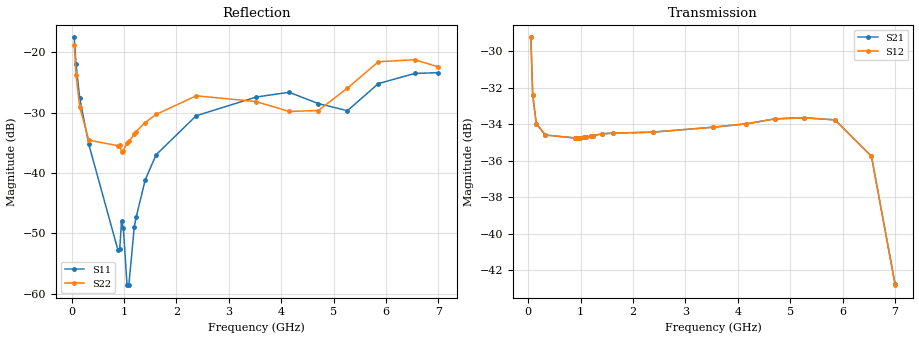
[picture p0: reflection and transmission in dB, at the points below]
! Integrated Device Technology
! Corporate Headquarters
! 6024 Silver Creek Valley Road
! San Jose, CA 95138  USA
! Phone:  1-408-284-8200
! Toll Free:  1-800-223-1366
! Webpage:  http://www.idt.com/
! Timing and RF Division
! 515 Groton Road, Suite 102
! Westford, MA 01886-6024
! Device:  F2258
! Description: Voltage Variable RF Attenuator
! Frequency:  50.0 -  6000.00 MHz
! Package:  3x3 mm Thin QFN Plastic Package: 16 pin
! Ports:  2 RF, 2 DC
!  Pin  1  = NC
!  Pin  2  = NC
!  Pin  3  = RF2  = Port 2
!  Pin  4  = GND
!  Pin  5  = Vdd
!  Pin  6  = NC
!  Pin  7  = VCTRL
!  Pin  8  = NC
!  Pin  9  = GND
!  Pin 10  = RF1  = Port 1
!  Pin 11  = NC
!  Pin 12  = NC
!  Pin 13  = NC
!  Pin 14  = NC
!  Pin 15  = NC
!  Pin 16  = NC
! Vcntrl:  1.940 Volts
! Vdd:  +3.300 Volts
! Current:  1.156 mA
! Data:  The device was measured on a the F2258 evaluation board which has
!  individual transmission lines to the RF pins.  Data was collected
!  using a calibrated network analyzer.  The evaluation board was
!  de-embedded using a TRL calibration technique.
!  The reference plane is the edge of the package pin.
! Misc:  SN 10
!  Action Tracker AT0285
! Date Measured:  2014-12-10
! Date:  2016-01-13  MJV
! Note:
!  Integrated Device Technology supplies this data as a sample of measured
!  data at the package pin for this product.  Your particular data for this
!  product may vary.
!  Data was taken at 25 degrees C.
!  Integrated Device Technology reserves the right to change this data at anytime.
!Freq_(GHz)  S11M_(dB)  S11P_(deg)  S21M_(dB)  S21P_(deg)  S12M_(dB)  S12P_(deg)  S22M_(dB)  S22P_(deg)
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# GHz S dB R 50
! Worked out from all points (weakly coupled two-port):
!   201 points, 50 MHz to 7 GHz, reference 50 ohm
!   highest |S21| = -29.24 dB at 50 MHz (marker M1); lowest = -42.8 dB at 7 GHz (marker M2)
!   lowest |S11| = -58.6 dB at 1.093 GHz (marker M3), VSWR 1.00, Z = 50 + j0.108 ohm
!   |S11| at or under -10 dB: start of sweep to end of sweep
!   |S22| runs from -36.5 to -18.8 dB; largest |S21 - S12| = 7.6e-05
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0.05  -17.55 -110.8  -29.24 -65.6  -29.24 -65.6  -18.84 -106.0
0.08475  -21.97 -107.3  -32.39 -46.3  -32.38 -46.3  -23.71 -93.8
0.15425  -27.56 -107.7  -33.97 -28.1  -33.97 -28.1  -29.05 -77.8
0.328  -35.25 -114.5  -34.59 -14.9  -34.59 -14.9  -34.56 -44.1
0.884  -52.74 166.5  -34.75 -8.8  -34.74 -8.8  -35.48 5.8
0.91875  -52.60 149.3  -34.74 -8.7  -34.74 -8.8  -35.44 6.6
0.9535  -47.87 -161.0  -34.75 -8.7  -34.74 -8.7  -36.49 16.7
0.98825  -49.13 -173.0  -34.73 -8.6  -34.73 -8.6  -36.29 14.9
1.05775  -58.54 155.9  -34.72 -8.5  -34.71 -8.5  -35.10 15.3
1.0925  -58.56 113.8  -34.70 -8.5  -34.69 -8.5  -34.76 15.3
1.19675  -48.86 54.7  -34.66 -8.7  -34.65 -8.7  -33.59 15.3
1.2315  -47.36 45.2  -34.63 -8.6  -34.63 -8.7  -33.14 14.7
1.40525  -41.12 33.0  -34.52 -9.4  -34.52 -9.4  -31.64 15.9
1.61375  -36.97 32.2  -34.49 -10.5  -34.48 -10.5  -30.30 13.7
2.37825  -30.52 47.9  -34.43 -14.5  -34.43 -14.5  -27.22 16.8
3.525  -27.42 91.5  -34.16 -21.5  -34.16 -21.4  -28.18 41.7
4.1505  -26.64 104.9  -33.98 -26.1  -33.98 -26.1  -29.81 51.6
4.7065  -28.50 95.4  -33.70 -30.8  -33.71 -30.8  -29.66 32.1
5.2625  -29.69 54.1  -33.64 -36.9  -33.65 -36.9  -25.96 -0.5
5.85325  -25.20 29.7  -33.76 -47.2  -33.76 -47.2  -21.58 -15.4
6.54825  -23.52 45.0  -35.75 -67.0  -35.76 -66.9  -21.25 -48.0
7  -23.39 84.4  -42.76 -63.1  -42.81 -62.8  -22.43 -126.7
